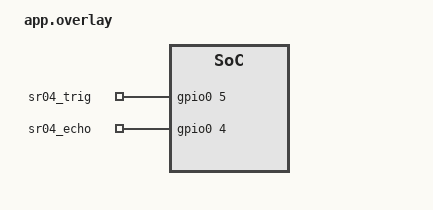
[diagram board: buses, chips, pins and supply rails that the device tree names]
/ {
    aliases {
        sr04-trig = &sr04_trig;
        sr04-echo = &sr04_echo;
    };

    sensors {
        compatible = "gpio-keys";

        sr04_trig: sr04_trig {
            gpios = <&gpio0 5 GPIO_ACTIVE_HIGH>;
        };
        sr04_echo: sr04_echo {
            gpios = <&gpio0 4 GPIO_ACTIVE_HIGH>;
        };
    };
};
